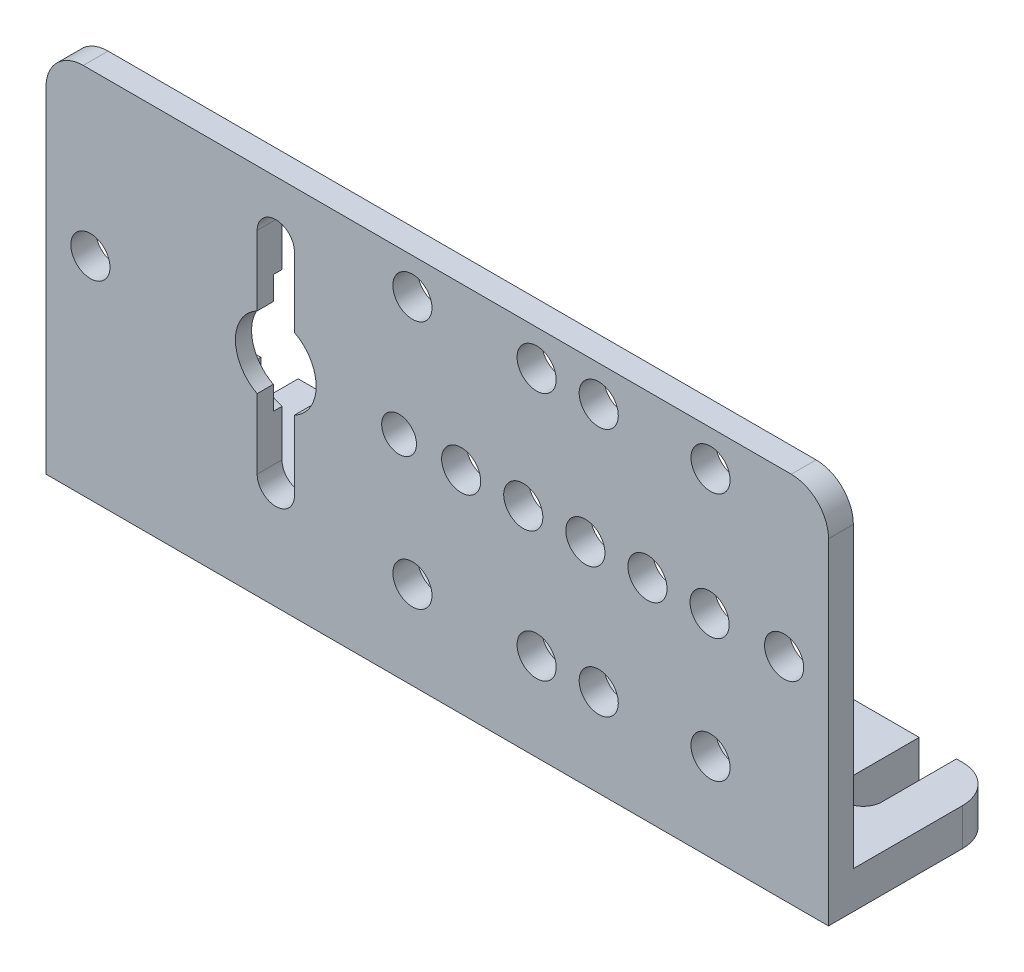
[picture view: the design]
ISO-10303-21;
HEADER;
FILE_DESCRIPTION(('STEP AP214'),'2;1');
FILE_NAME('part.step','',(''),(''),'','','');
FILE_SCHEMA(('AUTOMOTIVE_DESIGN { 1 0 10303 214 1 1 1 1 }'));
ENDSEC;
DATA;
#1=APPLICATION_CONTEXT('core data for automotive mechanical design processes');
#2=APPLICATION_PROTOCOL_DEFINITION('international standard','automotive_design',2000,#1);
#3=PRODUCT_CONTEXT('',#1,'mechanical');
#4=PRODUCT('Part','Part','',(#3));
#5=PRODUCT_RELATED_PRODUCT_CATEGORY('part','',(#4));
#6=PRODUCT_DEFINITION_FORMATION('','',#4);
#7=PRODUCT_DEFINITION_CONTEXT('part definition',#1,'design');
#8=PRODUCT_DEFINITION('design','',#6,#7);
#9=PRODUCT_DEFINITION_SHAPE('','',#8);
#10=(LENGTH_UNIT() NAMED_UNIT(*) SI_UNIT(.MILLI.,.METRE.));
#11=(NAMED_UNIT(*) PLANE_ANGLE_UNIT() SI_UNIT($,.RADIAN.));
#12=(NAMED_UNIT(*) SI_UNIT($,.STERADIAN.) SOLID_ANGLE_UNIT());
#13=UNCERTAINTY_MEASURE_WITH_UNIT(LENGTH_MEASURE(1.E-05),#10,'distance_accuracy_value','');
#14=(GEOMETRIC_REPRESENTATION_CONTEXT(3) GLOBAL_UNCERTAINTY_ASSIGNED_CONTEXT((#13)) GLOBAL_UNIT_ASSIGNED_CONTEXT((#10,
#11,#12)) REPRESENTATION_CONTEXT('',''));
#15=CARTESIAN_POINT('',(0.,0.,0.));
#16=DIRECTION('',(0.,0.,1.));
#17=DIRECTION('',(1.,0.,0.));
#18=AXIS2_PLACEMENT_3D('',#15,#16,#17);
#19=CARTESIAN_POINT('',(3.,3.,-13.8));
#20=DIRECTION('',(0.,0.,1.));
#21=DIRECTION('',(-1.,0.,0.));
#22=AXIS2_PLACEMENT_3D('',#19,#20,#21);
#23=PLANE('',#22);
#24=DIRECTION('',(1.,0.,0.));
#25=VECTOR('',#24,1.);
#26=CARTESIAN_POINT('',(3.,0.,-13.8));
#27=LINE('',#26,#25);
#28=CARTESIAN_POINT('',(6.5,0.,-13.8));
#29=VERTEX_POINT('',#28);
#30=CARTESIAN_POINT('',(56.5,0.,-13.8));
#31=VERTEX_POINT('',#30);
#32=EDGE_CURVE('E392',#29,#31,#27,.T.);
#33=ORIENTED_EDGE('',*,*,#32,.F.);
#34=DIRECTION('',(0.,1.,0.));
#35=VECTOR('',#34,1.);
#36=CARTESIAN_POINT('',(6.5,0.,-13.8));
#37=LINE('',#36,#35);
#38=CARTESIAN_POINT('',(6.5,3.,-13.8));
#39=VERTEX_POINT('',#38);
#40=EDGE_CURVE('E254',#29,#39,#37,.T.);
#41=ORIENTED_EDGE('',*,*,#40,.T.);
#42=DIRECTION('',(1.,0.,0.));
#43=VECTOR('',#42,1.);
#44=CARTESIAN_POINT('',(3.,3.,-13.8));
#45=LINE('',#44,#43);
#46=CARTESIAN_POINT('',(56.5,3.,-13.8));
#47=VERTEX_POINT('',#46);
#48=EDGE_CURVE('E236',#39,#47,#45,.T.);
#49=ORIENTED_EDGE('',*,*,#48,.T.);
#50=DIRECTION('',(0.,1.,0.));
#51=VECTOR('',#50,1.);
#52=CARTESIAN_POINT('',(56.5,0.,-13.8));
#53=LINE('',#52,#51);
#54=EDGE_CURVE('E244',#31,#47,#53,.T.);
#55=ORIENTED_EDGE('',*,*,#54,.F.);
#56=EDGE_LOOP('',(#33,#41,#49,#55));
#57=FACE_BOUND('',#56,.T.);
#58=ADVANCED_FACE('F35',(#57),#23,.F.);
#59=CARTESIAN_POINT('',(3.,0.,-13.8));
#60=VERTEX_POINT('',#59);
#61=CARTESIAN_POINT('',(3.5,0.,-13.8));
#62=VERTEX_POINT('',#61);
#63=EDGE_CURVE('E390',#60,#62,#27,.T.);
#64=ORIENTED_EDGE('',*,*,#63,.F.);
#65=DIRECTION('',(0.,-1.,0.));
#66=VECTOR('',#65,1.);
#67=CARTESIAN_POINT('',(3.,3.,-13.8));
#68=LINE('',#67,#66);
#69=CARTESIAN_POINT('',(3.,3.,-13.8));
#70=VERTEX_POINT('',#69);
#71=EDGE_CURVE('E369',#70,#60,#68,.T.);
#72=ORIENTED_EDGE('',*,*,#71,.F.);
#73=CARTESIAN_POINT('',(3.5,3.,-13.8));
#74=VERTEX_POINT('',#73);
#75=EDGE_CURVE('E255',#70,#74,#45,.T.);
#76=ORIENTED_EDGE('',*,*,#75,.T.);
#77=DIRECTION('',(0.,1.,0.));
#78=VECTOR('',#77,1.);
#79=CARTESIAN_POINT('',(3.5,0.,-13.8));
#80=LINE('',#79,#78);
#81=EDGE_CURVE('E484',#62,#74,#80,.T.);
#82=ORIENTED_EDGE('',*,*,#81,.F.);
#83=EDGE_LOOP('',(#64,#72,#76,#82));
#84=FACE_BOUND('',#83,.T.);
#85=ADVANCED_FACE('F629',(#84),#23,.F.);
#86=CARTESIAN_POINT('',(60.,27.,-2.));
#87=DIRECTION('',(0.,0.,1.));
#88=DIRECTION('',(-1.,0.,0.));
#89=AXIS2_PLACEMENT_3D('',#86,#87,#88);
#90=CYLINDRICAL_SURFACE('',#89,3.);
#91=CARTESIAN_POINT('',(60.,27.,0.));
#92=DIRECTION('',(0.,0.,1.));
#93=DIRECTION('',(1.,0.,0.));
#94=AXIS2_PLACEMENT_3D('',#91,#92,#93);
#95=CIRCLE('',#94,3.);
#96=CARTESIAN_POINT('',(63.,27.,0.));
#97=VERTEX_POINT('',#96);
#98=CARTESIAN_POINT('',(60.,30.,0.));
#99=VERTEX_POINT('',#98);
#100=EDGE_CURVE('E339',#97,#99,#95,.T.);
#101=ORIENTED_EDGE('',*,*,#100,.F.);
#102=DIRECTION('',(0.,0.,1.));
#103=VECTOR('',#102,1.);
#104=CARTESIAN_POINT('',(63.,27.,-2.));
#105=LINE('',#104,#103);
#106=CARTESIAN_POINT('',(63.,27.,-2.));
#107=VERTEX_POINT('',#106);
#108=EDGE_CURVE('E312',#107,#97,#105,.T.);
#109=ORIENTED_EDGE('',*,*,#108,.F.);
#110=CARTESIAN_POINT('',(60.,27.,-2.));
#111=DIRECTION('',(0.,0.,1.));
#112=DIRECTION('',(1.,0.,0.));
#113=AXIS2_PLACEMENT_3D('',#110,#111,#112);
#114=CIRCLE('',#113,3.);
#115=CARTESIAN_POINT('',(60.,30.,-2.));
#116=VERTEX_POINT('',#115);
#117=EDGE_CURVE('E346',#107,#116,#114,.T.);
#118=ORIENTED_EDGE('',*,*,#117,.T.);
#119=DIRECTION('',(0.,0.,1.));
#120=VECTOR('',#119,1.);
#121=CARTESIAN_POINT('',(60.,30.,-2.));
#122=LINE('',#121,#120);
#123=EDGE_CURVE('E288',#116,#99,#122,.T.);
#124=ORIENTED_EDGE('',*,*,#123,.T.);
#125=EDGE_LOOP('',(#101,#109,#118,#124));
#126=FACE_BOUND('',#125,.T.);
#127=ADVANCED_FACE('F37',(#126),#90,.T.);
#128=CARTESIAN_POINT('',(3.,30.,-2.));
#129=DIRECTION('',(0.,-1.,0.));
#130=DIRECTION('',(1.,0.,0.));
#131=AXIS2_PLACEMENT_3D('',#128,#129,#130);
#132=PLANE('',#131);
#133=DIRECTION('',(-1.,0.,0.));
#134=VECTOR('',#133,1.);
#135=CARTESIAN_POINT('',(3.,30.,0.));
#136=LINE('',#135,#134);
#137=CARTESIAN_POINT('',(3.,30.,0.));
#138=VERTEX_POINT('',#137);
#139=EDGE_CURVE('E335',#99,#138,#136,.T.);
#140=ORIENTED_EDGE('',*,*,#139,.F.);
#141=ORIENTED_EDGE('',*,*,#123,.F.);
#142=DIRECTION('',(-1.,0.,0.));
#143=VECTOR('',#142,1.);
#144=CARTESIAN_POINT('',(3.,30.,-2.));
#145=LINE('',#144,#143);
#146=CARTESIAN_POINT('',(3.,30.,-2.));
#147=VERTEX_POINT('',#146);
#148=EDGE_CURVE('E347',#116,#147,#145,.T.);
#149=ORIENTED_EDGE('',*,*,#148,.T.);
#150=DIRECTION('',(0.,0.,1.));
#151=VECTOR('',#150,1.);
#152=CARTESIAN_POINT('',(3.,30.,-2.));
#153=LINE('',#152,#151);
#154=EDGE_CURVE('E292',#147,#138,#153,.T.);
#155=ORIENTED_EDGE('',*,*,#154,.T.);
#156=EDGE_LOOP('',(#140,#141,#149,#155));
#157=FACE_BOUND('',#156,.T.);
#158=ADVANCED_FACE('F350',(#157),#132,.F.);
#159=CARTESIAN_POINT('',(3.,27.,-2.));
#160=DIRECTION('',(0.,0.,1.));
#161=DIRECTION('',(-1.,0.,0.));
#162=AXIS2_PLACEMENT_3D('',#159,#160,#161);
#163=CYLINDRICAL_SURFACE('',#162,3.);
#164=CARTESIAN_POINT('',(3.,27.,0.));
#165=DIRECTION('',(0.,0.,1.));
#166=DIRECTION('',(-1.,0.,0.));
#167=AXIS2_PLACEMENT_3D('',#164,#165,#166);
#168=CIRCLE('',#167,3.);
#169=CARTESIAN_POINT('',(0.,27.,0.));
#170=VERTEX_POINT('',#169);
#171=EDGE_CURVE('E327',#138,#170,#168,.T.);
#172=ORIENTED_EDGE('',*,*,#171,.F.);
#173=ORIENTED_EDGE('',*,*,#154,.F.);
#174=CARTESIAN_POINT('',(3.,27.,-2.));
#175=DIRECTION('',(0.,0.,1.));
#176=DIRECTION('',(-1.,0.,0.));
#177=AXIS2_PLACEMENT_3D('',#174,#175,#176);
#178=CIRCLE('',#177,3.);
#179=CARTESIAN_POINT('',(0.,27.,-2.));
#180=VERTEX_POINT('',#179);
#181=EDGE_CURVE('E306',#147,#180,#178,.T.);
#182=ORIENTED_EDGE('',*,*,#181,.T.);
#183=DIRECTION('',(0.,0.,1.));
#184=VECTOR('',#183,1.);
#185=CARTESIAN_POINT('',(0.,27.,-2.));
#186=LINE('',#185,#184);
#187=EDGE_CURVE('E300',#180,#170,#186,.T.);
#188=ORIENTED_EDGE('',*,*,#187,.T.);
#189=EDGE_LOOP('',(#172,#173,#182,#188));
#190=FACE_BOUND('',#189,.T.);
#191=ADVANCED_FACE('F325',(#190),#163,.T.);
#192=CARTESIAN_POINT('',(0.,0.,-2.));
#193=DIRECTION('',(1.,0.,0.));
#194=DIRECTION('',(0.,0.,1.));
#195=AXIS2_PLACEMENT_3D('',#192,#193,#194);
#196=PLANE('',#195);
#197=DIRECTION('',(0.,-1.,0.));
#198=VECTOR('',#197,1.);
#199=CARTESIAN_POINT('',(0.,0.,0.));
#200=LINE('',#199,#198);
#201=CARTESIAN_POINT('',(0.,0.,0.));
#202=VERTEX_POINT('',#201);
#203=EDGE_CURVE('E334',#170,#202,#200,.T.);
#204=ORIENTED_EDGE('',*,*,#203,.F.);
#205=ORIENTED_EDGE('',*,*,#187,.F.);
#206=DIRECTION('',(0.,-1.,0.));
#207=VECTOR('',#206,1.);
#208=CARTESIAN_POINT('',(0.,0.,-2.));
#209=LINE('',#208,#207);
#210=CARTESIAN_POINT('',(0.,3.,-2.));
#211=VERTEX_POINT('',#210);
#212=EDGE_CURVE('E303',#180,#211,#209,.T.);
#213=ORIENTED_EDGE('',*,*,#212,.T.);
#214=DIRECTION('',(0.,0.,-1.));
#215=VECTOR('',#214,1.);
#216=CARTESIAN_POINT('',(0.,3.,-2.));
#217=LINE('',#216,#215);
#218=CARTESIAN_POINT('',(0.,3.,-10.8));
#219=VERTEX_POINT('',#218);
#220=EDGE_CURVE('E278',#211,#219,#217,.T.);
#221=ORIENTED_EDGE('',*,*,#220,.T.);
#222=DIRECTION('',(0.,-1.,0.));
#223=VECTOR('',#222,1.);
#224=CARTESIAN_POINT('',(0.,3.,-10.8));
#225=LINE('',#224,#223);
#226=CARTESIAN_POINT('',(0.,0.,-10.8));
#227=VERTEX_POINT('',#226);
#228=EDGE_CURVE('E360',#219,#227,#225,.T.);
#229=ORIENTED_EDGE('',*,*,#228,.T.);
#230=DIRECTION('',(0.,0.,1.));
#231=VECTOR('',#230,1.);
#232=CARTESIAN_POINT('',(0.,0.,-2.));
#233=LINE('',#232,#231);
#234=EDGE_CURVE('E318',#227,#202,#233,.T.);
#235=ORIENTED_EDGE('',*,*,#234,.T.);
#236=EDGE_LOOP('',(#204,#205,#213,#221,#229,#235));
#237=FACE_BOUND('',#236,.T.);
#238=ADVANCED_FACE('F357',(#237),#196,.F.);
#239=CARTESIAN_POINT('',(63.,0.,-2.));
#240=DIRECTION('',(0.,1.,0.));
#241=DIRECTION('',(-1.,0.,0.));
#242=AXIS2_PLACEMENT_3D('',#239,#240,#241);
#243=PLANE('',#242);
#244=CARTESIAN_POINT('',(58.,0.,-7.8));
#245=DIRECTION('',(0.,-1.,0.));
#246=DIRECTION('',(0.,0.,-1.));
#247=AXIS2_PLACEMENT_3D('',#244,#245,#246);
#248=CIRCLE('',#247,1.5);
#249=CARTESIAN_POINT('',(59.5,0.,-7.8));
#250=VERTEX_POINT('',#249);
#251=CARTESIAN_POINT('',(56.5,0.,-7.8));
#252=VERTEX_POINT('',#251);
#253=EDGE_CURVE('E252',#250,#252,#248,.T.);
#254=ORIENTED_EDGE('',*,*,#253,.F.);
#255=DIRECTION('',(0.,0.,1.));
#256=VECTOR('',#255,1.);
#257=CARTESIAN_POINT('',(59.5,0.,-7.8));
#258=LINE('',#257,#256);
#259=CARTESIAN_POINT('',(59.5,0.,-13.8));
#260=VERTEX_POINT('',#259);
#261=EDGE_CURVE('E513',#260,#250,#258,.T.);
#262=ORIENTED_EDGE('',*,*,#261,.F.);
#263=CARTESIAN_POINT('',(60.,0.,-13.8));
#264=VERTEX_POINT('',#263);
#265=EDGE_CURVE('E389',#260,#264,#27,.T.);
#266=ORIENTED_EDGE('',*,*,#265,.T.);
#267=CARTESIAN_POINT('',(60.,0.,-10.8));
#268=DIRECTION('',(0.,-1.,0.));
#269=DIRECTION('',(0.,0.,1.));
#270=AXIS2_PLACEMENT_3D('',#267,#268,#269);
#271=CIRCLE('',#270,3.);
#272=CARTESIAN_POINT('',(63.,0.,-10.8));
#273=VERTEX_POINT('',#272);
#274=EDGE_CURVE('E281',#264,#273,#271,.T.);
#275=ORIENTED_EDGE('',*,*,#274,.T.);
#276=DIRECTION('',(0.,0.,1.));
#277=VECTOR('',#276,1.);
#278=CARTESIAN_POINT('',(63.,0.,-2.));
#279=LINE('',#278,#277);
#280=CARTESIAN_POINT('',(63.,0.,0.));
#281=VERTEX_POINT('',#280);
#282=EDGE_CURVE('E315',#273,#281,#279,.T.);
#283=ORIENTED_EDGE('',*,*,#282,.T.);
#284=DIRECTION('',(1.,0.,0.));
#285=VECTOR('',#284,1.);
#286=CARTESIAN_POINT('',(63.,0.,0.));
#287=LINE('',#286,#285);
#288=EDGE_CURVE('E337',#202,#281,#287,.T.);
#289=ORIENTED_EDGE('',*,*,#288,.F.);
#290=ORIENTED_EDGE('',*,*,#234,.F.);
#291=CARTESIAN_POINT('',(3.,0.,-10.8));
#292=DIRECTION('',(0.,-1.,0.));
#293=DIRECTION('',(0.,0.,1.));
#294=AXIS2_PLACEMENT_3D('',#291,#292,#293);
#295=CIRCLE('',#294,3.);
#296=EDGE_CURVE('E367',#227,#60,#295,.T.);
#297=ORIENTED_EDGE('',*,*,#296,.T.);
#298=ORIENTED_EDGE('',*,*,#63,.T.);
#299=DIRECTION('',(0.,0.,-1.));
#300=VECTOR('',#299,1.);
#301=CARTESIAN_POINT('',(3.5,0.,-13.8));
#302=LINE('',#301,#300);
#303=CARTESIAN_POINT('',(3.5,0.,-7.8));
#304=VERTEX_POINT('',#303);
#305=EDGE_CURVE('E487',#304,#62,#302,.T.);
#306=ORIENTED_EDGE('',*,*,#305,.F.);
#307=CARTESIAN_POINT('',(5.,0.,-7.8));
#308=DIRECTION('',(0.,-1.,0.));
#309=DIRECTION('',(0.,0.,1.));
#310=AXIS2_PLACEMENT_3D('',#307,#308,#309);
#311=CIRCLE('',#310,1.5);
#312=CARTESIAN_POINT('',(6.5,0.,-7.8));
#313=VERTEX_POINT('',#312);
#314=EDGE_CURVE('E494',#313,#304,#311,.T.);
#315=ORIENTED_EDGE('',*,*,#314,.F.);
#316=DIRECTION('',(0.,0.,1.));
#317=VECTOR('',#316,1.);
#318=CARTESIAN_POINT('',(6.5,0.,-13.8));
#319=LINE('',#318,#317);
#320=EDGE_CURVE('E497',#29,#313,#319,.T.);
#321=ORIENTED_EDGE('',*,*,#320,.F.);
#322=ORIENTED_EDGE('',*,*,#32,.T.);
#323=DIRECTION('',(0.,0.,-1.));
#324=VECTOR('',#323,1.);
#325=CARTESIAN_POINT('',(56.5,0.,-13.8));
#326=LINE('',#325,#324);
#327=EDGE_CURVE('E247',#252,#31,#326,.T.);
#328=ORIENTED_EDGE('',*,*,#327,.F.);
#329=EDGE_LOOP('',(#254,#262,#266,#275,#283,#289,#290,#297,#298,#306,#315,#321,#322,#328));
#330=FACE_BOUND('',#329,.T.);
#331=ADVANCED_FACE('F387',(#330),#243,.F.);
#332=CARTESIAN_POINT('',(63.,27.,-2.));
#333=DIRECTION('',(-1.,0.,0.));
#334=DIRECTION('',(0.,0.,-1.));
#335=AXIS2_PLACEMENT_3D('',#332,#333,#334);
#336=PLANE('',#335);
#337=DIRECTION('',(0.,1.,0.));
#338=VECTOR('',#337,1.);
#339=CARTESIAN_POINT('',(63.,27.,0.));
#340=LINE('',#339,#338);
#341=EDGE_CURVE('E344',#281,#97,#340,.T.);
#342=ORIENTED_EDGE('',*,*,#341,.F.);
#343=ORIENTED_EDGE('',*,*,#282,.F.);
#344=DIRECTION('',(0.,-1.,0.));
#345=VECTOR('',#344,1.);
#346=CARTESIAN_POINT('',(63.,3.,-10.8));
#347=LINE('',#346,#345);
#348=CARTESIAN_POINT('',(63.,3.,-10.8));
#349=VERTEX_POINT('',#348);
#350=EDGE_CURVE('E269',#349,#273,#347,.T.);
#351=ORIENTED_EDGE('',*,*,#350,.F.);
#352=DIRECTION('',(0.,0.,1.));
#353=VECTOR('',#352,1.);
#354=CARTESIAN_POINT('',(63.,3.,-2.));
#355=LINE('',#354,#353);
#356=CARTESIAN_POINT('',(63.,3.,-2.));
#357=VERTEX_POINT('',#356);
#358=EDGE_CURVE('E266',#349,#357,#355,.T.);
#359=ORIENTED_EDGE('',*,*,#358,.T.);
#360=DIRECTION('',(0.,1.,0.));
#361=VECTOR('',#360,1.);
#362=CARTESIAN_POINT('',(63.,27.,-2.));
#363=LINE('',#362,#361);
#364=EDGE_CURVE('E275',#357,#107,#363,.T.);
#365=ORIENTED_EDGE('',*,*,#364,.T.);
#366=ORIENTED_EDGE('',*,*,#108,.T.);
#367=EDGE_LOOP('',(#342,#343,#351,#359,#365,#366));
#368=FACE_BOUND('',#367,.T.);
#369=ADVANCED_FACE('F384',(#368),#336,.F.);
#370=CARTESIAN_POINT('',(60.,27.,-2.));
#371=DIRECTION('',(0.,0.,-1.));
#372=DIRECTION('',(1.,0.,0.));
#373=AXIS2_PLACEMENT_3D('',#370,#371,#372);
#374=PLANE('',#373);
#375=CARTESIAN_POINT('',(53.5,7.075,-2.));
#376=DIRECTION('',(0.,0.,1.));
#377=DIRECTION('',(1.,0.,0.));
#378=AXIS2_PLACEMENT_3D('',#375,#376,#377);
#379=CIRCLE('',#378,1.575);
#380=CARTESIAN_POINT('',(55.075,7.075,-2.));
#381=VERTEX_POINT('',#380);
#382=EDGE_CURVE('E611',#381,#381,#379,.T.);
#383=ORIENTED_EDGE('',*,*,#382,.T.);
#384=EDGE_LOOP('',(#383));
#385=FACE_BOUND('',#384,.T.);
#386=CARTESIAN_POINT('',(53.5,27.125,-2.));
#387=DIRECTION('',(0.,0.,1.));
#388=DIRECTION('',(1.,0.,0.));
#389=AXIS2_PLACEMENT_3D('',#386,#387,#388);
#390=CIRCLE('',#389,1.575);
#391=CARTESIAN_POINT('',(55.075,27.125,-2.));
#392=VERTEX_POINT('',#391);
#393=EDGE_CURVE('E605',#392,#392,#390,.T.);
#394=ORIENTED_EDGE('',*,*,#393,.T.);
#395=EDGE_LOOP('',(#394));
#396=FACE_BOUND('',#395,.T.);
#397=CARTESIAN_POINT('',(59.425,17.,-2.));
#398=DIRECTION('',(0.,0.,1.));
#399=DIRECTION('',(1.,0.,0.));
#400=AXIS2_PLACEMENT_3D('',#397,#398,#399);
#401=CIRCLE('',#400,1.575);
#402=CARTESIAN_POINT('',(61.,17.,-2.));
#403=VERTEX_POINT('',#402);
#404=EDGE_CURVE('E599',#403,#403,#401,.T.);
#405=ORIENTED_EDGE('',*,*,#404,.T.);
#406=EDGE_LOOP('',(#405));
#407=FACE_BOUND('',#406,.T.);
#408=CARTESIAN_POINT('',(44.5,27.125,-2.));
#409=DIRECTION('',(0.,0.,1.));
#410=DIRECTION('',(1.,0.,0.));
#411=AXIS2_PLACEMENT_3D('',#408,#409,#410);
#412=CIRCLE('',#411,1.57499999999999);
#413=CARTESIAN_POINT('',(46.075,27.125,-2.));
#414=VERTEX_POINT('',#413);
#415=EDGE_CURVE('E593',#414,#414,#412,.T.);
#416=ORIENTED_EDGE('',*,*,#415,.T.);
#417=EDGE_LOOP('',(#416));
#418=FACE_BOUND('',#417,.T.);
#419=CARTESIAN_POINT('',(39.5,27.125,-2.));
#420=DIRECTION('',(0.,0.,1.));
#421=DIRECTION('',(1.,0.,0.));
#422=AXIS2_PLACEMENT_3D('',#419,#420,#421);
#423=CIRCLE('',#422,1.575);
#424=CARTESIAN_POINT('',(41.075,27.125,-2.));
#425=VERTEX_POINT('',#424);
#426=EDGE_CURVE('E587',#425,#425,#423,.T.);
#427=ORIENTED_EDGE('',*,*,#426,.T.);
#428=EDGE_LOOP('',(#427));
#429=FACE_BOUND('',#428,.T.);
#430=CARTESIAN_POINT('',(29.5,27.125,-2.));
#431=DIRECTION('',(0.,0.,1.));
#432=DIRECTION('',(1.,0.,0.));
#433=AXIS2_PLACEMENT_3D('',#430,#431,#432);
#434=CIRCLE('',#433,1.575);
#435=CARTESIAN_POINT('',(31.075,27.125,-2.));
#436=VERTEX_POINT('',#435);
#437=EDGE_CURVE('E581',#436,#436,#434,.T.);
#438=ORIENTED_EDGE('',*,*,#437,.T.);
#439=EDGE_LOOP('',(#438));
#440=FACE_BOUND('',#439,.T.);
#441=CARTESIAN_POINT('',(29.5,7.075,-2.));
#442=DIRECTION('',(0.,0.,1.));
#443=DIRECTION('',(1.,0.,0.));
#444=AXIS2_PLACEMENT_3D('',#441,#442,#443);
#445=CIRCLE('',#444,1.575);
#446=CARTESIAN_POINT('',(31.075,7.075,-2.));
#447=VERTEX_POINT('',#446);
#448=EDGE_CURVE('E575',#447,#447,#445,.T.);
#449=ORIENTED_EDGE('',*,*,#448,.T.);
#450=EDGE_LOOP('',(#449));
#451=FACE_BOUND('',#450,.T.);
#452=CARTESIAN_POINT('',(39.5,7.075,-2.));
#453=DIRECTION('',(0.,0.,1.));
#454=DIRECTION('',(1.,0.,0.));
#455=AXIS2_PLACEMENT_3D('',#452,#453,#454);
#456=CIRCLE('',#455,1.575);
#457=CARTESIAN_POINT('',(41.075,7.075,-2.));
#458=VERTEX_POINT('',#457);
#459=EDGE_CURVE('E569',#458,#458,#456,.T.);
#460=ORIENTED_EDGE('',*,*,#459,.T.);
#461=EDGE_LOOP('',(#460));
#462=FACE_BOUND('',#461,.T.);
#463=CARTESIAN_POINT('',(44.5,7.075,-2.));
#464=DIRECTION('',(0.,0.,1.));
#465=DIRECTION('',(1.,0.,0.));
#466=AXIS2_PLACEMENT_3D('',#463,#464,#465);
#467=CIRCLE('',#466,1.57499999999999);
#468=CARTESIAN_POINT('',(46.075,7.075,-2.));
#469=VERTEX_POINT('',#468);
#470=EDGE_CURVE('E563',#469,#469,#467,.T.);
#471=ORIENTED_EDGE('',*,*,#470,.T.);
#472=EDGE_LOOP('',(#471));
#473=FACE_BOUND('',#472,.T.);
#474=CARTESIAN_POINT('',(53.425,17.,-2.));
#475=DIRECTION('',(0.,0.,1.));
#476=DIRECTION('',(1.,0.,0.));
#477=AXIS2_PLACEMENT_3D('',#474,#475,#476);
#478=CIRCLE('',#477,1.575);
#479=CARTESIAN_POINT('',(55.,17.,-2.));
#480=VERTEX_POINT('',#479);
#481=EDGE_CURVE('E557',#480,#480,#478,.T.);
#482=ORIENTED_EDGE('',*,*,#481,.T.);
#483=EDGE_LOOP('',(#482));
#484=FACE_BOUND('',#483,.T.);
#485=CARTESIAN_POINT('',(48.425,17.,-2.));
#486=DIRECTION('',(0.,0.,1.));
#487=DIRECTION('',(1.,0.,0.));
#488=AXIS2_PLACEMENT_3D('',#485,#486,#487);
#489=CIRCLE('',#488,1.575);
#490=CARTESIAN_POINT('',(50.,17.,-2.));
#491=VERTEX_POINT('',#490);
#492=EDGE_CURVE('E551',#491,#491,#489,.T.);
#493=ORIENTED_EDGE('',*,*,#492,.T.);
#494=EDGE_LOOP('',(#493));
#495=FACE_BOUND('',#494,.T.);
#496=CARTESIAN_POINT('',(43.425,17.,-2.));
#497=DIRECTION('',(0.,0.,1.));
#498=DIRECTION('',(1.,0.,0.));
#499=AXIS2_PLACEMENT_3D('',#496,#497,#498);
#500=CIRCLE('',#499,1.575);
#501=CARTESIAN_POINT('',(45.,17.,-2.));
#502=VERTEX_POINT('',#501);
#503=EDGE_CURVE('E545',#502,#502,#500,.T.);
#504=ORIENTED_EDGE('',*,*,#503,.T.);
#505=EDGE_LOOP('',(#504));
#506=FACE_BOUND('',#505,.T.);
#507=CARTESIAN_POINT('',(38.425,17.,-2.));
#508=DIRECTION('',(0.,0.,1.));
#509=DIRECTION('',(1.,0.,0.));
#510=AXIS2_PLACEMENT_3D('',#507,#508,#509);
#511=CIRCLE('',#510,1.575);
#512=CARTESIAN_POINT('',(40.,17.,-2.));
#513=VERTEX_POINT('',#512);
#514=EDGE_CURVE('E539',#513,#513,#511,.T.);
#515=ORIENTED_EDGE('',*,*,#514,.T.);
#516=EDGE_LOOP('',(#515));
#517=FACE_BOUND('',#516,.T.);
#518=CARTESIAN_POINT('',(33.425,17.,-2.));
#519=DIRECTION('',(0.,0.,1.));
#520=DIRECTION('',(1.,0.,0.));
#521=AXIS2_PLACEMENT_3D('',#518,#519,#520);
#522=CIRCLE('',#521,1.575);
#523=CARTESIAN_POINT('',(35.,17.,-2.));
#524=VERTEX_POINT('',#523);
#525=EDGE_CURVE('E533',#524,#524,#522,.T.);
#526=ORIENTED_EDGE('',*,*,#525,.T.);
#527=EDGE_LOOP('',(#526));
#528=FACE_BOUND('',#527,.T.);
#529=CARTESIAN_POINT('',(28.425,17.,-2.));
#530=DIRECTION('',(0.,0.,1.));
#531=DIRECTION('',(1.,0.,0.));
#532=AXIS2_PLACEMENT_3D('',#529,#530,#531);
#533=CIRCLE('',#532,1.4);
#534=CARTESIAN_POINT('',(29.825,17.,-2.));
#535=VERTEX_POINT('',#534);
#536=EDGE_CURVE('E527',#535,#535,#533,.T.);
#537=ORIENTED_EDGE('',*,*,#536,.T.);
#538=EDGE_LOOP('',(#537));
#539=FACE_BOUND('',#538,.T.);
#540=CARTESIAN_POINT('',(3.575,17.,-2.));
#541=DIRECTION('',(0.,0.,1.));
#542=DIRECTION('',(1.,0.,0.));
#543=AXIS2_PLACEMENT_3D('',#540,#541,#542);
#544=CIRCLE('',#543,1.575);
#545=CARTESIAN_POINT('',(5.15,17.,-2.));
#546=VERTEX_POINT('',#545);
#547=EDGE_CURVE('E521',#546,#546,#544,.T.);
#548=ORIENTED_EDGE('',*,*,#547,.T.);
#549=EDGE_LOOP('',(#548));
#550=FACE_BOUND('',#549,.T.);
#551=CARTESIAN_POINT('',(18.5,17.,-2.));
#552=DIRECTION('',(0.,0.,1.));
#553=DIRECTION('',(1.,0.,0.));
#554=AXIS2_PLACEMENT_3D('',#551,#552,#553);
#555=CIRCLE('',#554,5.00000000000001);
#556=CARTESIAN_POINT('',(17.,21.7696960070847,-2.));
#557=VERTEX_POINT('',#556);
#558=CARTESIAN_POINT('',(17.,12.2303039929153,-2.));
#559=VERTEX_POINT('',#558);
#560=EDGE_CURVE('E477',#557,#559,#555,.T.);
#561=ORIENTED_EDGE('',*,*,#560,.T.);
#562=DIRECTION('',(0.,-1.,0.));
#563=VECTOR('',#562,1.);
#564=CARTESIAN_POINT('',(17.,14.1168593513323,-2.));
#565=LINE('',#564,#563);
#566=CARTESIAN_POINT('',(17.,8.50000000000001,-2.));
#567=VERTEX_POINT('',#566);
#568=EDGE_CURVE('E455',#559,#567,#565,.T.);
#569=ORIENTED_EDGE('',*,*,#568,.T.);
#570=CARTESIAN_POINT('',(18.5,8.50000000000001,-2.));
#571=DIRECTION('',(0.,0.,1.));
#572=DIRECTION('',(1.,0.,0.));
#573=AXIS2_PLACEMENT_3D('',#570,#571,#572);
#574=CIRCLE('',#573,1.5);
#575=CARTESIAN_POINT('',(20.,8.50000000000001,-2.));
#576=VERTEX_POINT('',#575);
#577=EDGE_CURVE('E452',#567,#576,#574,.T.);
#578=ORIENTED_EDGE('',*,*,#577,.T.);
#579=DIRECTION('',(0.,1.,0.));
#580=VECTOR('',#579,1.);
#581=CARTESIAN_POINT('',(20.,14.1168593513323,-2.));
#582=LINE('',#581,#580);
#583=CARTESIAN_POINT('',(20.,12.2303039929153,-2.));
#584=VERTEX_POINT('',#583);
#585=EDGE_CURVE('E449',#576,#584,#582,.T.);
#586=ORIENTED_EDGE('',*,*,#585,.T.);
#587=CARTESIAN_POINT('',(20.,21.7696960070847,-2.));
#588=VERTEX_POINT('',#587);
#589=EDGE_CURVE('E478',#584,#588,#555,.T.);
#590=ORIENTED_EDGE('',*,*,#589,.T.);
#591=DIRECTION('',(0.,1.,0.));
#592=VECTOR('',#591,1.);
#593=CARTESIAN_POINT('',(20.,25.5,-2.));
#594=LINE('',#593,#592);
#595=CARTESIAN_POINT('',(20.,25.5,-2.));
#596=VERTEX_POINT('',#595);
#597=EDGE_CURVE('E446',#588,#596,#594,.T.);
#598=ORIENTED_EDGE('',*,*,#597,.T.);
#599=CARTESIAN_POINT('',(18.5,25.5,-2.));
#600=DIRECTION('',(0.,0.,1.));
#601=DIRECTION('',(1.,0.,0.));
#602=AXIS2_PLACEMENT_3D('',#599,#600,#601);
#603=CIRCLE('',#602,1.5);
#604=CARTESIAN_POINT('',(17.,25.5,-2.));
#605=VERTEX_POINT('',#604);
#606=EDGE_CURVE('E443',#596,#605,#603,.T.);
#607=ORIENTED_EDGE('',*,*,#606,.T.);
#608=DIRECTION('',(0.,-1.,0.));
#609=VECTOR('',#608,1.);
#610=CARTESIAN_POINT('',(17.,25.5,-2.));
#611=LINE('',#610,#609);
#612=EDGE_CURVE('E440',#605,#557,#611,.T.);
#613=ORIENTED_EDGE('',*,*,#612,.T.);
#614=EDGE_LOOP('',(#561,#569,#578,#586,#590,#598,#607,#613));
#615=FACE_BOUND('',#614,.T.);
#616=DIRECTION('',(-1.,0.,0.));
#617=VECTOR('',#616,1.);
#618=CARTESIAN_POINT('',(0.,3.,-2.));
#619=LINE('',#618,#617);
#620=EDGE_CURVE('E272',#357,#211,#619,.T.);
#621=ORIENTED_EDGE('',*,*,#620,.T.);
#622=ORIENTED_EDGE('',*,*,#212,.F.);
#623=ORIENTED_EDGE('',*,*,#181,.F.);
#624=ORIENTED_EDGE('',*,*,#148,.F.);
#625=ORIENTED_EDGE('',*,*,#117,.F.);
#626=ORIENTED_EDGE('',*,*,#364,.F.);
#627=EDGE_LOOP('',(#621,#622,#623,#624,#625,#626));
#628=FACE_BOUND('',#627,.T.);
#629=ADVANCED_FACE('F353',(#385,#396,#407,#418,#429,#440,#451,#462,#473,#484,#495,#506,#517,
#528,#539,#550,#615,#628),#374,.T.);
#630=CARTESIAN_POINT('',(60.,27.,0.));
#631=DIRECTION('',(0.,0.,-1.));
#632=DIRECTION('',(1.,0.,0.));
#633=AXIS2_PLACEMENT_3D('',#630,#631,#632);
#634=PLANE('',#633);
#635=CARTESIAN_POINT('',(53.5,7.075,0.));
#636=DIRECTION('',(0.,0.,1.));
#637=DIRECTION('',(1.,0.,0.));
#638=AXIS2_PLACEMENT_3D('',#635,#636,#637);
#639=CIRCLE('',#638,1.575);
#640=CARTESIAN_POINT('',(55.075,7.075,0.));
#641=VERTEX_POINT('',#640);
#642=EDGE_CURVE('E608',#641,#641,#639,.T.);
#643=ORIENTED_EDGE('',*,*,#642,.F.);
#644=EDGE_LOOP('',(#643));
#645=FACE_BOUND('',#644,.T.);
#646=CARTESIAN_POINT('',(53.5,27.125,0.));
#647=DIRECTION('',(0.,0.,1.));
#648=DIRECTION('',(1.,0.,0.));
#649=AXIS2_PLACEMENT_3D('',#646,#647,#648);
#650=CIRCLE('',#649,1.575);
#651=CARTESIAN_POINT('',(55.075,27.125,0.));
#652=VERTEX_POINT('',#651);
#653=EDGE_CURVE('E602',#652,#652,#650,.T.);
#654=ORIENTED_EDGE('',*,*,#653,.F.);
#655=EDGE_LOOP('',(#654));
#656=FACE_BOUND('',#655,.T.);
#657=CARTESIAN_POINT('',(59.425,17.,0.));
#658=DIRECTION('',(0.,0.,1.));
#659=DIRECTION('',(1.,0.,0.));
#660=AXIS2_PLACEMENT_3D('',#657,#658,#659);
#661=CIRCLE('',#660,1.575);
#662=CARTESIAN_POINT('',(61.,17.,0.));
#663=VERTEX_POINT('',#662);
#664=EDGE_CURVE('E596',#663,#663,#661,.T.);
#665=ORIENTED_EDGE('',*,*,#664,.F.);
#666=EDGE_LOOP('',(#665));
#667=FACE_BOUND('',#666,.T.);
#668=CARTESIAN_POINT('',(44.5,27.125,0.));
#669=DIRECTION('',(0.,0.,1.));
#670=DIRECTION('',(1.,0.,0.));
#671=AXIS2_PLACEMENT_3D('',#668,#669,#670);
#672=CIRCLE('',#671,1.57499999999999);
#673=CARTESIAN_POINT('',(46.075,27.125,0.));
#674=VERTEX_POINT('',#673);
#675=EDGE_CURVE('E590',#674,#674,#672,.T.);
#676=ORIENTED_EDGE('',*,*,#675,.F.);
#677=EDGE_LOOP('',(#676));
#678=FACE_BOUND('',#677,.T.);
#679=CARTESIAN_POINT('',(39.5,27.125,0.));
#680=DIRECTION('',(0.,0.,1.));
#681=DIRECTION('',(1.,0.,0.));
#682=AXIS2_PLACEMENT_3D('',#679,#680,#681);
#683=CIRCLE('',#682,1.575);
#684=CARTESIAN_POINT('',(41.075,27.125,0.));
#685=VERTEX_POINT('',#684);
#686=EDGE_CURVE('E584',#685,#685,#683,.T.);
#687=ORIENTED_EDGE('',*,*,#686,.F.);
#688=EDGE_LOOP('',(#687));
#689=FACE_BOUND('',#688,.T.);
#690=CARTESIAN_POINT('',(29.5,27.125,0.));
#691=DIRECTION('',(0.,0.,1.));
#692=DIRECTION('',(1.,0.,0.));
#693=AXIS2_PLACEMENT_3D('',#690,#691,#692);
#694=CIRCLE('',#693,1.575);
#695=CARTESIAN_POINT('',(31.075,27.125,0.));
#696=VERTEX_POINT('',#695);
#697=EDGE_CURVE('E578',#696,#696,#694,.T.);
#698=ORIENTED_EDGE('',*,*,#697,.F.);
#699=EDGE_LOOP('',(#698));
#700=FACE_BOUND('',#699,.T.);
#701=CARTESIAN_POINT('',(29.5,7.075,0.));
#702=DIRECTION('',(0.,0.,1.));
#703=DIRECTION('',(1.,0.,0.));
#704=AXIS2_PLACEMENT_3D('',#701,#702,#703);
#705=CIRCLE('',#704,1.575);
#706=CARTESIAN_POINT('',(31.075,7.075,0.));
#707=VERTEX_POINT('',#706);
#708=EDGE_CURVE('E572',#707,#707,#705,.T.);
#709=ORIENTED_EDGE('',*,*,#708,.F.);
#710=EDGE_LOOP('',(#709));
#711=FACE_BOUND('',#710,.T.);
#712=CARTESIAN_POINT('',(39.5,7.075,0.));
#713=DIRECTION('',(0.,0.,1.));
#714=DIRECTION('',(1.,0.,0.));
#715=AXIS2_PLACEMENT_3D('',#712,#713,#714);
#716=CIRCLE('',#715,1.575);
#717=CARTESIAN_POINT('',(41.075,7.075,0.));
#718=VERTEX_POINT('',#717);
#719=EDGE_CURVE('E566',#718,#718,#716,.T.);
#720=ORIENTED_EDGE('',*,*,#719,.F.);
#721=EDGE_LOOP('',(#720));
#722=FACE_BOUND('',#721,.T.);
#723=CARTESIAN_POINT('',(44.5,7.075,0.));
#724=DIRECTION('',(0.,0.,1.));
#725=DIRECTION('',(1.,0.,0.));
#726=AXIS2_PLACEMENT_3D('',#723,#724,#725);
#727=CIRCLE('',#726,1.57499999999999);
#728=CARTESIAN_POINT('',(46.075,7.075,0.));
#729=VERTEX_POINT('',#728);
#730=EDGE_CURVE('E560',#729,#729,#727,.T.);
#731=ORIENTED_EDGE('',*,*,#730,.F.);
#732=EDGE_LOOP('',(#731));
#733=FACE_BOUND('',#732,.T.);
#734=CARTESIAN_POINT('',(53.425,17.,0.));
#735=DIRECTION('',(0.,0.,1.));
#736=DIRECTION('',(1.,0.,0.));
#737=AXIS2_PLACEMENT_3D('',#734,#735,#736);
#738=CIRCLE('',#737,1.575);
#739=CARTESIAN_POINT('',(55.,17.,0.));
#740=VERTEX_POINT('',#739);
#741=EDGE_CURVE('E554',#740,#740,#738,.T.);
#742=ORIENTED_EDGE('',*,*,#741,.F.);
#743=EDGE_LOOP('',(#742));
#744=FACE_BOUND('',#743,.T.);
#745=CARTESIAN_POINT('',(48.425,17.,0.));
#746=DIRECTION('',(0.,0.,1.));
#747=DIRECTION('',(1.,0.,0.));
#748=AXIS2_PLACEMENT_3D('',#745,#746,#747);
#749=CIRCLE('',#748,1.575);
#750=CARTESIAN_POINT('',(50.,17.,0.));
#751=VERTEX_POINT('',#750);
#752=EDGE_CURVE('E548',#751,#751,#749,.T.);
#753=ORIENTED_EDGE('',*,*,#752,.F.);
#754=EDGE_LOOP('',(#753));
#755=FACE_BOUND('',#754,.T.);
#756=CARTESIAN_POINT('',(43.425,17.,0.));
#757=DIRECTION('',(0.,0.,1.));
#758=DIRECTION('',(1.,0.,0.));
#759=AXIS2_PLACEMENT_3D('',#756,#757,#758);
#760=CIRCLE('',#759,1.575);
#761=CARTESIAN_POINT('',(45.,17.,0.));
#762=VERTEX_POINT('',#761);
#763=EDGE_CURVE('E542',#762,#762,#760,.T.);
#764=ORIENTED_EDGE('',*,*,#763,.F.);
#765=EDGE_LOOP('',(#764));
#766=FACE_BOUND('',#765,.T.);
#767=CARTESIAN_POINT('',(38.425,17.,0.));
#768=DIRECTION('',(0.,0.,1.));
#769=DIRECTION('',(1.,0.,0.));
#770=AXIS2_PLACEMENT_3D('',#767,#768,#769);
#771=CIRCLE('',#770,1.575);
#772=CARTESIAN_POINT('',(40.,17.,0.));
#773=VERTEX_POINT('',#772);
#774=EDGE_CURVE('E536',#773,#773,#771,.T.);
#775=ORIENTED_EDGE('',*,*,#774,.F.);
#776=EDGE_LOOP('',(#775));
#777=FACE_BOUND('',#776,.T.);
#778=CARTESIAN_POINT('',(33.425,17.,0.));
#779=DIRECTION('',(0.,0.,1.));
#780=DIRECTION('',(1.,0.,0.));
#781=AXIS2_PLACEMENT_3D('',#778,#779,#780);
#782=CIRCLE('',#781,1.575);
#783=CARTESIAN_POINT('',(35.,17.,0.));
#784=VERTEX_POINT('',#783);
#785=EDGE_CURVE('E530',#784,#784,#782,.T.);
#786=ORIENTED_EDGE('',*,*,#785,.F.);
#787=EDGE_LOOP('',(#786));
#788=FACE_BOUND('',#787,.T.);
#789=CARTESIAN_POINT('',(28.425,17.,0.));
#790=DIRECTION('',(0.,0.,1.));
#791=DIRECTION('',(1.,0.,0.));
#792=AXIS2_PLACEMENT_3D('',#789,#790,#791);
#793=CIRCLE('',#792,1.4);
#794=CARTESIAN_POINT('',(29.825,17.,0.));
#795=VERTEX_POINT('',#794);
#796=EDGE_CURVE('E524',#795,#795,#793,.T.);
#797=ORIENTED_EDGE('',*,*,#796,.F.);
#798=EDGE_LOOP('',(#797));
#799=FACE_BOUND('',#798,.T.);
#800=CARTESIAN_POINT('',(3.575,17.,0.));
#801=DIRECTION('',(0.,0.,1.));
#802=DIRECTION('',(1.,0.,0.));
#803=AXIS2_PLACEMENT_3D('',#800,#801,#802);
#804=CIRCLE('',#803,1.575);
#805=CARTESIAN_POINT('',(5.15,17.,0.));
#806=VERTEX_POINT('',#805);
#807=EDGE_CURVE('E241',#806,#806,#804,.T.);
#808=ORIENTED_EDGE('',*,*,#807,.F.);
#809=EDGE_LOOP('',(#808));
#810=FACE_BOUND('',#809,.T.);
#811=DIRECTION('',(0.,-1.,0.));
#812=VECTOR('',#811,1.);
#813=CARTESIAN_POINT('',(17.,25.5,0.));
#814=LINE('',#813,#812);
#815=CARTESIAN_POINT('',(17.,25.5,0.));
#816=VERTEX_POINT('',#815);
#817=CARTESIAN_POINT('',(17.,19.8831406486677,0.));
#818=VERTEX_POINT('',#817);
#819=EDGE_CURVE('E401',#816,#818,#814,.T.);
#820=ORIENTED_EDGE('',*,*,#819,.F.);
#821=CARTESIAN_POINT('',(18.5,25.5,0.));
#822=DIRECTION('',(0.,0.,1.));
#823=DIRECTION('',(1.,0.,0.));
#824=AXIS2_PLACEMENT_3D('',#821,#822,#823);
#825=CIRCLE('',#824,1.5);
#826=CARTESIAN_POINT('',(20.,25.5,0.));
#827=VERTEX_POINT('',#826);
#828=EDGE_CURVE('E419',#827,#816,#825,.T.);
#829=ORIENTED_EDGE('',*,*,#828,.F.);
#830=DIRECTION('',(0.,1.,0.));
#831=VECTOR('',#830,1.);
#832=CARTESIAN_POINT('',(20.,25.5,0.));
#833=LINE('',#832,#831);
#834=CARTESIAN_POINT('',(20.,19.8831406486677,0.));
#835=VERTEX_POINT('',#834);
#836=EDGE_CURVE('E422',#835,#827,#833,.T.);
#837=ORIENTED_EDGE('',*,*,#836,.F.);
#838=CARTESIAN_POINT('',(18.5,17.,0.));
#839=DIRECTION('',(0.,0.,1.));
#840=DIRECTION('',(1.,0.,0.));
#841=AXIS2_PLACEMENT_3D('',#838,#839,#840);
#842=CIRCLE('',#841,3.25);
#843=CARTESIAN_POINT('',(20.,14.1168593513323,0.));
#844=VERTEX_POINT('',#843);
#845=EDGE_CURVE('E425',#844,#835,#842,.T.);
#846=ORIENTED_EDGE('',*,*,#845,.F.);
#847=DIRECTION('',(0.,1.,0.));
#848=VECTOR('',#847,1.);
#849=CARTESIAN_POINT('',(20.,14.1168593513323,0.));
#850=LINE('',#849,#848);
#851=CARTESIAN_POINT('',(20.,8.50000000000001,0.));
#852=VERTEX_POINT('',#851);
#853=EDGE_CURVE('E428',#852,#844,#850,.T.);
#854=ORIENTED_EDGE('',*,*,#853,.F.);
#855=CARTESIAN_POINT('',(18.5,8.50000000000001,0.));
#856=DIRECTION('',(0.,0.,1.));
#857=DIRECTION('',(1.,0.,0.));
#858=AXIS2_PLACEMENT_3D('',#855,#856,#857);
#859=CIRCLE('',#858,1.5);
#860=CARTESIAN_POINT('',(17.,8.50000000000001,0.));
#861=VERTEX_POINT('',#860);
#862=EDGE_CURVE('E431',#861,#852,#859,.T.);
#863=ORIENTED_EDGE('',*,*,#862,.F.);
#864=DIRECTION('',(0.,-1.,0.));
#865=VECTOR('',#864,1.);
#866=CARTESIAN_POINT('',(17.,14.1168593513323,0.));
#867=LINE('',#866,#865);
#868=CARTESIAN_POINT('',(17.,14.1168593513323,0.));
#869=VERTEX_POINT('',#868);
#870=EDGE_CURVE('E434',#869,#861,#867,.T.);
#871=ORIENTED_EDGE('',*,*,#870,.F.);
#872=CARTESIAN_POINT('',(18.5,17.,0.));
#873=DIRECTION('',(0.,0.,1.));
#874=DIRECTION('',(1.,0.,0.));
#875=AXIS2_PLACEMENT_3D('',#872,#873,#874);
#876=CIRCLE('',#875,3.25);
#877=EDGE_CURVE('E437',#818,#869,#876,.T.);
#878=ORIENTED_EDGE('',*,*,#877,.F.);
#879=EDGE_LOOP('',(#820,#829,#837,#846,#854,#863,#871,#878));
#880=FACE_BOUND('',#879,.T.);
#881=ORIENTED_EDGE('',*,*,#100,.T.);
#882=ORIENTED_EDGE('',*,*,#139,.T.);
#883=ORIENTED_EDGE('',*,*,#171,.T.);
#884=ORIENTED_EDGE('',*,*,#203,.T.);
#885=ORIENTED_EDGE('',*,*,#288,.T.);
#886=ORIENTED_EDGE('',*,*,#341,.T.);
#887=EDGE_LOOP('',(#881,#882,#883,#884,#885,#886));
#888=FACE_BOUND('',#887,.T.);
#889=ADVANCED_FACE('F332',(#645,#656,#667,#678,#689,#700,#711,#722,#733,#744,#755,#766,#777,
#788,#799,#810,#880,#888),#634,.F.);
#890=CARTESIAN_POINT('',(3.,3.,-10.8));
#891=DIRECTION('',(0.,-1.,0.));
#892=DIRECTION('',(0.,0.,1.));
#893=AXIS2_PLACEMENT_3D('',#890,#891,#892);
#894=CYLINDRICAL_SURFACE('',#893,3.);
#895=ORIENTED_EDGE('',*,*,#296,.F.);
#896=ORIENTED_EDGE('',*,*,#228,.F.);
#897=CARTESIAN_POINT('',(3.,3.,-10.8));
#898=DIRECTION('',(0.,-1.,0.));
#899=DIRECTION('',(0.,0.,1.));
#900=AXIS2_PLACEMENT_3D('',#897,#898,#899);
#901=CIRCLE('',#900,3.);
#902=EDGE_CURVE('E261',#219,#70,#901,.T.);
#903=ORIENTED_EDGE('',*,*,#902,.T.);
#904=ORIENTED_EDGE('',*,*,#71,.T.);
#905=EDGE_LOOP('',(#895,#896,#903,#904));
#906=FACE_BOUND('',#905,.T.);
#907=ADVANCED_FACE('F366',(#906),#894,.T.);
#908=CARTESIAN_POINT('',(59.5,3.,-13.8));
#909=VERTEX_POINT('',#908);
#910=CARTESIAN_POINT('',(60.,3.,-13.8));
#911=VERTEX_POINT('',#910);
#912=EDGE_CURVE('E256',#909,#911,#45,.T.);
#913=ORIENTED_EDGE('',*,*,#912,.T.);
#914=DIRECTION('',(0.,-1.,0.));
#915=VECTOR('',#914,1.);
#916=CARTESIAN_POINT('',(60.,3.,-13.8));
#917=LINE('',#916,#915);
#918=EDGE_CURVE('E371',#911,#264,#917,.T.);
#919=ORIENTED_EDGE('',*,*,#918,.T.);
#920=ORIENTED_EDGE('',*,*,#265,.F.);
#921=DIRECTION('',(0.,1.,0.));
#922=VECTOR('',#921,1.);
#923=CARTESIAN_POINT('',(59.5,0.,-13.8));
#924=LINE('',#923,#922);
#925=EDGE_CURVE('E251',#260,#909,#924,.T.);
#926=ORIENTED_EDGE('',*,*,#925,.T.);
#927=EDGE_LOOP('',(#913,#919,#920,#926));
#928=FACE_BOUND('',#927,.T.);
#929=ADVANCED_FACE('F631',(#928),#23,.F.);
#930=CARTESIAN_POINT('',(60.,3.,-10.8));
#931=DIRECTION('',(0.,-1.,0.));
#932=DIRECTION('',(0.,0.,1.));
#933=AXIS2_PLACEMENT_3D('',#930,#931,#932);
#934=CYLINDRICAL_SURFACE('',#933,3.);
#935=ORIENTED_EDGE('',*,*,#274,.F.);
#936=ORIENTED_EDGE('',*,*,#918,.F.);
#937=CARTESIAN_POINT('',(60.,3.,-10.8));
#938=DIRECTION('',(0.,-1.,0.));
#939=DIRECTION('',(0.,0.,1.));
#940=AXIS2_PLACEMENT_3D('',#937,#938,#939);
#941=CIRCLE('',#940,3.);
#942=EDGE_CURVE('E259',#911,#349,#941,.T.);
#943=ORIENTED_EDGE('',*,*,#942,.T.);
#944=ORIENTED_EDGE('',*,*,#350,.T.);
#945=EDGE_LOOP('',(#935,#936,#943,#944));
#946=FACE_BOUND('',#945,.T.);
#947=ADVANCED_FACE('F380',(#946),#934,.T.);
#948=CARTESIAN_POINT('',(3.,3.,-10.8));
#949=DIRECTION('',(0.,-1.,0.));
#950=DIRECTION('',(0.,0.,1.));
#951=AXIS2_PLACEMENT_3D('',#948,#949,#950);
#952=PLANE('',#951);
#953=ORIENTED_EDGE('',*,*,#48,.F.);
#954=DIRECTION('',(0.,0.,1.));
#955=VECTOR('',#954,1.);
#956=CARTESIAN_POINT('',(6.5,3.,-13.8));
#957=LINE('',#956,#955);
#958=CARTESIAN_POINT('',(6.5,3.,-7.8));
#959=VERTEX_POINT('',#958);
#960=EDGE_CURVE('E58',#39,#959,#957,.T.);
#961=ORIENTED_EDGE('',*,*,#960,.T.);
#962=CARTESIAN_POINT('',(5.,3.,-7.8));
#963=DIRECTION('',(0.,-1.,0.));
#964=DIRECTION('',(0.,0.,1.));
#965=AXIS2_PLACEMENT_3D('',#962,#963,#964);
#966=CIRCLE('',#965,1.5);
#967=CARTESIAN_POINT('',(3.5,3.,-7.8));
#968=VERTEX_POINT('',#967);
#969=EDGE_CURVE('E502',#959,#968,#966,.T.);
#970=ORIENTED_EDGE('',*,*,#969,.T.);
#971=DIRECTION('',(0.,0.,-1.));
#972=VECTOR('',#971,1.);
#973=CARTESIAN_POINT('',(3.5,3.,-13.8));
#974=LINE('',#973,#972);
#975=EDGE_CURVE('E500',#968,#74,#974,.T.);
#976=ORIENTED_EDGE('',*,*,#975,.T.);
#977=ORIENTED_EDGE('',*,*,#75,.F.);
#978=ORIENTED_EDGE('',*,*,#902,.F.);
#979=ORIENTED_EDGE('',*,*,#220,.F.);
#980=ORIENTED_EDGE('',*,*,#620,.F.);
#981=ORIENTED_EDGE('',*,*,#358,.F.);
#982=ORIENTED_EDGE('',*,*,#942,.F.);
#983=ORIENTED_EDGE('',*,*,#912,.F.);
#984=DIRECTION('',(0.,0.,1.));
#985=VECTOR('',#984,1.);
#986=CARTESIAN_POINT('',(59.5,3.,-7.8));
#987=LINE('',#986,#985);
#988=CARTESIAN_POINT('',(59.5,3.,-7.8));
#989=VERTEX_POINT('',#988);
#990=EDGE_CURVE('E50',#909,#989,#987,.T.);
#991=ORIENTED_EDGE('',*,*,#990,.T.);
#992=CARTESIAN_POINT('',(58.,3.,-7.8));
#993=DIRECTION('',(0.,-1.,0.));
#994=DIRECTION('',(0.,0.,-1.));
#995=AXIS2_PLACEMENT_3D('',#992,#993,#994);
#996=CIRCLE('',#995,1.5);
#997=CARTESIAN_POINT('',(56.5,3.,-7.8));
#998=VERTEX_POINT('',#997);
#999=EDGE_CURVE('E239',#989,#998,#996,.T.);
#1000=ORIENTED_EDGE('',*,*,#999,.T.);
#1001=DIRECTION('',(0.,0.,-1.));
#1002=VECTOR('',#1001,1.);
#1003=CARTESIAN_POINT('',(56.5,3.,-13.8));
#1004=LINE('',#1003,#1002);
#1005=EDGE_CURVE('E232',#998,#47,#1004,.T.);
#1006=ORIENTED_EDGE('',*,*,#1005,.T.);
#1007=EDGE_LOOP('',(#953,#961,#970,#976,#977,#978,#979,#980,#981,#982,#983,#991,#1000,#1006));
#1008=FACE_BOUND('',#1007,.T.);
#1009=ADVANCED_FACE('F234',(#1008),#952,.F.);
#1010=CARTESIAN_POINT('',(18.5,17.,0.));
#1011=DIRECTION('',(0.,0.,-1.));
#1012=DIRECTION('',(1.,0.,0.));
#1013=AXIS2_PLACEMENT_3D('',#1010,#1011,#1012);
#1014=CYLINDRICAL_SURFACE('',#1013,3.25);
#1015=DIRECTION('',(0.,0.,-1.));
#1016=VECTOR('',#1015,1.);
#1017=CARTESIAN_POINT('',(17.,19.8831406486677,0.));
#1018=LINE('',#1017,#1016);
#1019=CARTESIAN_POINT('',(17.,19.8831406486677,-1.29999999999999));
#1020=VERTEX_POINT('',#1019);
#1021=EDGE_CURVE('E396',#818,#1020,#1018,.T.);
#1022=ORIENTED_EDGE('',*,*,#1021,.F.);
#1023=ORIENTED_EDGE('',*,*,#877,.T.);
#1024=DIRECTION('',(0.,0.,-1.));
#1025=VECTOR('',#1024,1.);
#1026=CARTESIAN_POINT('',(17.,14.1168593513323,0.));
#1027=LINE('',#1026,#1025);
#1028=CARTESIAN_POINT('',(17.,14.1168593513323,-1.29999999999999));
#1029=VERTEX_POINT('',#1028);
#1030=EDGE_CURVE('E397',#869,#1029,#1027,.T.);
#1031=ORIENTED_EDGE('',*,*,#1030,.T.);
#1032=CARTESIAN_POINT('',(18.5,17.,-1.29999999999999));
#1033=DIRECTION('',(0.,0.,-1.));
#1034=DIRECTION('',(-1.,0.,0.));
#1035=AXIS2_PLACEMENT_3D('',#1032,#1033,#1034);
#1036=CIRCLE('',#1035,3.25);
#1037=EDGE_CURVE('E475',#1020,#1029,#1036,.F.);
#1038=ORIENTED_EDGE('',*,*,#1037,.F.);
#1039=EDGE_LOOP('',(#1022,#1023,#1031,#1038));
#1040=FACE_BOUND('',#1039,.T.);
#1041=ADVANCED_FACE('F692',(#1040),#1014,.F.);
#1042=CARTESIAN_POINT('',(17.,25.5,0.));
#1043=DIRECTION('',(-1.,0.,0.));
#1044=DIRECTION('',(0.,-1.,0.));
#1045=AXIS2_PLACEMENT_3D('',#1042,#1043,#1044);
#1046=PLANE('',#1045);
#1047=ORIENTED_EDGE('',*,*,#612,.F.);
#1048=DIRECTION('',(0.,0.,-1.));
#1049=VECTOR('',#1048,1.);
#1050=CARTESIAN_POINT('',(17.,25.5,0.));
#1051=LINE('',#1050,#1049);
#1052=EDGE_CURVE('E413',#816,#605,#1051,.T.);
#1053=ORIENTED_EDGE('',*,*,#1052,.F.);
#1054=ORIENTED_EDGE('',*,*,#819,.T.);
#1055=ORIENTED_EDGE('',*,*,#1021,.T.);
#1056=DIRECTION('',(0.,-1.,0.));
#1057=VECTOR('',#1056,1.);
#1058=CARTESIAN_POINT('',(17.,25.5,-1.29999999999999));
#1059=LINE('',#1058,#1057);
#1060=CARTESIAN_POINT('',(17.,21.7696960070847,-1.29999999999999));
#1061=VERTEX_POINT('',#1060);
#1062=EDGE_CURVE('E473',#1061,#1020,#1059,.T.);
#1063=ORIENTED_EDGE('',*,*,#1062,.F.);
#1064=DIRECTION('',(0.,0.,-1.));
#1065=VECTOR('',#1064,1.);
#1066=CARTESIAN_POINT('',(17.,21.7696960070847,-2.));
#1067=LINE('',#1066,#1065);
#1068=EDGE_CURVE('E458',#557,#1061,#1067,.F.);
#1069=ORIENTED_EDGE('',*,*,#1068,.F.);
#1070=EDGE_LOOP('',(#1047,#1053,#1054,#1055,#1063,#1069));
#1071=FACE_BOUND('',#1070,.T.);
#1072=ADVANCED_FACE('F688',(#1071),#1046,.F.);
#1073=CARTESIAN_POINT('',(18.5,25.5,0.));
#1074=DIRECTION('',(0.,0.,-1.));
#1075=DIRECTION('',(1.,0.,0.));
#1076=AXIS2_PLACEMENT_3D('',#1073,#1074,#1075);
#1077=CYLINDRICAL_SURFACE('',#1076,1.5);
#1078=ORIENTED_EDGE('',*,*,#606,.F.);
#1079=DIRECTION('',(0.,0.,-1.));
#1080=VECTOR('',#1079,1.);
#1081=CARTESIAN_POINT('',(20.,25.5,0.));
#1082=LINE('',#1081,#1080);
#1083=EDGE_CURVE('E411',#827,#596,#1082,.T.);
#1084=ORIENTED_EDGE('',*,*,#1083,.F.);
#1085=ORIENTED_EDGE('',*,*,#828,.T.);
#1086=ORIENTED_EDGE('',*,*,#1052,.T.);
#1087=EDGE_LOOP('',(#1078,#1084,#1085,#1086));
#1088=FACE_BOUND('',#1087,.T.);
#1089=ADVANCED_FACE('F691',(#1088),#1077,.F.);
#1090=CARTESIAN_POINT('',(20.,25.5,0.));
#1091=DIRECTION('',(1.,0.,0.));
#1092=DIRECTION('',(0.,0.,1.));
#1093=AXIS2_PLACEMENT_3D('',#1090,#1091,#1092);
#1094=PLANE('',#1093);
#1095=DIRECTION('',(0.,1.,0.));
#1096=VECTOR('',#1095,1.);
#1097=CARTESIAN_POINT('',(20.,25.5,-1.29999999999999));
#1098=LINE('',#1097,#1096);
#1099=CARTESIAN_POINT('',(20.,19.8831406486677,-1.29999999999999));
#1100=VERTEX_POINT('',#1099);
#1101=CARTESIAN_POINT('',(20.,21.7696960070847,-1.29999999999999));
#1102=VERTEX_POINT('',#1101);
#1103=EDGE_CURVE('E466',#1100,#1102,#1098,.T.);
#1104=ORIENTED_EDGE('',*,*,#1103,.F.);
#1105=DIRECTION('',(0.,0.,-1.));
#1106=VECTOR('',#1105,1.);
#1107=CARTESIAN_POINT('',(20.,19.8831406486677,0.));
#1108=LINE('',#1107,#1106);
#1109=EDGE_CURVE('E408',#835,#1100,#1108,.T.);
#1110=ORIENTED_EDGE('',*,*,#1109,.F.);
#1111=ORIENTED_EDGE('',*,*,#836,.T.);
#1112=ORIENTED_EDGE('',*,*,#1083,.T.);
#1113=ORIENTED_EDGE('',*,*,#597,.F.);
#1114=DIRECTION('',(0.,0.,-1.));
#1115=VECTOR('',#1114,1.);
#1116=CARTESIAN_POINT('',(20.,21.7696960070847,-2.));
#1117=LINE('',#1116,#1115);
#1118=EDGE_CURVE('E461',#1102,#588,#1117,.T.);
#1119=ORIENTED_EDGE('',*,*,#1118,.F.);
#1120=EDGE_LOOP('',(#1104,#1110,#1111,#1112,#1113,#1119));
#1121=FACE_BOUND('',#1120,.T.);
#1122=ADVANCED_FACE('F696',(#1121),#1094,.F.);
#1123=CARTESIAN_POINT('',(18.5,17.,0.));
#1124=DIRECTION('',(0.,0.,-1.));
#1125=DIRECTION('',(1.,0.,0.));
#1126=AXIS2_PLACEMENT_3D('',#1123,#1124,#1125);
#1127=CYLINDRICAL_SURFACE('',#1126,3.25);
#1128=DIRECTION('',(0.,0.,-1.));
#1129=VECTOR('',#1128,1.);
#1130=CARTESIAN_POINT('',(20.,14.1168593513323,0.));
#1131=LINE('',#1130,#1129);
#1132=CARTESIAN_POINT('',(20.,14.1168593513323,-1.29999999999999));
#1133=VERTEX_POINT('',#1132);
#1134=EDGE_CURVE('E405',#844,#1133,#1131,.T.);
#1135=ORIENTED_EDGE('',*,*,#1134,.F.);
#1136=ORIENTED_EDGE('',*,*,#845,.T.);
#1137=ORIENTED_EDGE('',*,*,#1109,.T.);
#1138=CARTESIAN_POINT('',(18.5,17.,-1.29999999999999));
#1139=DIRECTION('',(0.,0.,-1.));
#1140=DIRECTION('',(-1.,0.,0.));
#1141=AXIS2_PLACEMENT_3D('',#1138,#1139,#1140);
#1142=CIRCLE('',#1141,3.25);
#1143=EDGE_CURVE('E469',#1133,#1100,#1142,.F.);
#1144=ORIENTED_EDGE('',*,*,#1143,.F.);
#1145=EDGE_LOOP('',(#1135,#1136,#1137,#1144));
#1146=FACE_BOUND('',#1145,.T.);
#1147=ADVANCED_FACE('F700',(#1146),#1127,.F.);
#1148=CARTESIAN_POINT('',(20.,14.1168593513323,0.));
#1149=DIRECTION('',(1.,0.,0.));
#1150=DIRECTION('',(0.,0.,1.));
#1151=AXIS2_PLACEMENT_3D('',#1148,#1149,#1150);
#1152=PLANE('',#1151);
#1153=ORIENTED_EDGE('',*,*,#585,.F.);
#1154=DIRECTION('',(0.,0.,-1.));
#1155=VECTOR('',#1154,1.);
#1156=CARTESIAN_POINT('',(20.,8.50000000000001,0.));
#1157=LINE('',#1156,#1155);
#1158=EDGE_CURVE('E403',#852,#576,#1157,.T.);
#1159=ORIENTED_EDGE('',*,*,#1158,.F.);
#1160=ORIENTED_EDGE('',*,*,#853,.T.);
#1161=ORIENTED_EDGE('',*,*,#1134,.T.);
#1162=DIRECTION('',(0.,1.,0.));
#1163=VECTOR('',#1162,1.);
#1164=CARTESIAN_POINT('',(20.,14.1168593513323,-1.29999999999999));
#1165=LINE('',#1164,#1163);
#1166=CARTESIAN_POINT('',(20.,12.2303039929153,-1.29999999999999));
#1167=VERTEX_POINT('',#1166);
#1168=EDGE_CURVE('E471',#1167,#1133,#1165,.T.);
#1169=ORIENTED_EDGE('',*,*,#1168,.F.);
#1170=DIRECTION('',(0.,0.,-1.));
#1171=VECTOR('',#1170,1.);
#1172=CARTESIAN_POINT('',(20.,12.2303039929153,-2.));
#1173=LINE('',#1172,#1171);
#1174=EDGE_CURVE('E463',#584,#1167,#1173,.F.);
#1175=ORIENTED_EDGE('',*,*,#1174,.F.);
#1176=EDGE_LOOP('',(#1153,#1159,#1160,#1161,#1169,#1175));
#1177=FACE_BOUND('',#1176,.T.);
#1178=ADVANCED_FACE('F704',(#1177),#1152,.F.);
#1179=CARTESIAN_POINT('',(18.5,8.50000000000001,0.));
#1180=DIRECTION('',(0.,0.,-1.));
#1181=DIRECTION('',(1.,0.,0.));
#1182=AXIS2_PLACEMENT_3D('',#1179,#1180,#1181);
#1183=CYLINDRICAL_SURFACE('',#1182,1.5);
#1184=ORIENTED_EDGE('',*,*,#577,.F.);
#1185=DIRECTION('',(0.,0.,-1.));
#1186=VECTOR('',#1185,1.);
#1187=CARTESIAN_POINT('',(17.,8.50000000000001,0.));
#1188=LINE('',#1187,#1186);
#1189=EDGE_CURVE('E400',#861,#567,#1188,.T.);
#1190=ORIENTED_EDGE('',*,*,#1189,.F.);
#1191=ORIENTED_EDGE('',*,*,#862,.T.);
#1192=ORIENTED_EDGE('',*,*,#1158,.T.);
#1193=EDGE_LOOP('',(#1184,#1190,#1191,#1192));
#1194=FACE_BOUND('',#1193,.T.);
#1195=ADVANCED_FACE('F708',(#1194),#1183,.F.);
#1196=CARTESIAN_POINT('',(17.,14.1168593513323,0.));
#1197=DIRECTION('',(-1.,0.,0.));
#1198=DIRECTION('',(0.,0.,-1.));
#1199=AXIS2_PLACEMENT_3D('',#1196,#1197,#1198);
#1200=PLANE('',#1199);
#1201=DIRECTION('',(0.,-1.,0.));
#1202=VECTOR('',#1201,1.);
#1203=CARTESIAN_POINT('',(17.,14.1168593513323,-1.29999999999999));
#1204=LINE('',#1203,#1202);
#1205=CARTESIAN_POINT('',(17.,12.2303039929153,-1.29999999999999));
#1206=VERTEX_POINT('',#1205);
#1207=EDGE_CURVE('E43',#1029,#1206,#1204,.T.);
#1208=ORIENTED_EDGE('',*,*,#1207,.F.);
#1209=ORIENTED_EDGE('',*,*,#1030,.F.);
#1210=ORIENTED_EDGE('',*,*,#870,.T.);
#1211=ORIENTED_EDGE('',*,*,#1189,.T.);
#1212=ORIENTED_EDGE('',*,*,#568,.F.);
#1213=DIRECTION('',(0.,0.,-1.));
#1214=VECTOR('',#1213,1.);
#1215=CARTESIAN_POINT('',(17.,12.2303039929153,-2.));
#1216=LINE('',#1215,#1214);
#1217=EDGE_CURVE('E11',#1206,#559,#1216,.T.);
#1218=ORIENTED_EDGE('',*,*,#1217,.F.);
#1219=EDGE_LOOP('',(#1208,#1209,#1210,#1211,#1212,#1218));
#1220=FACE_BOUND('',#1219,.T.);
#1221=ADVANCED_FACE('F712',(#1220),#1200,.F.);
#1222=CARTESIAN_POINT('',(18.5,17.,-1.29999999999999));
#1223=DIRECTION('',(0.,0.,1.));
#1224=DIRECTION('',(-1.,0.,0.));
#1225=AXIS2_PLACEMENT_3D('',#1222,#1223,#1224);
#1226=PLANE('',#1225);
#1227=CARTESIAN_POINT('',(18.5,17.,-1.29999999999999));
#1228=DIRECTION('',(0.,0.,1.));
#1229=DIRECTION('',(1.,0.,0.));
#1230=AXIS2_PLACEMENT_3D('',#1227,#1228,#1229);
#1231=CIRCLE('',#1230,5.00000000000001);
#1232=EDGE_CURVE('E481',#1061,#1206,#1231,.T.);
#1233=ORIENTED_EDGE('',*,*,#1232,.F.);
#1234=ORIENTED_EDGE('',*,*,#1062,.T.);
#1235=ORIENTED_EDGE('',*,*,#1037,.T.);
#1236=ORIENTED_EDGE('',*,*,#1207,.T.);
#1237=EDGE_LOOP('',(#1233,#1234,#1235,#1236));
#1238=FACE_BOUND('',#1237,.T.);
#1239=ADVANCED_FACE('F683',(#1238),#1226,.F.);
#1240=CARTESIAN_POINT('',(18.5,17.,-2.));
#1241=DIRECTION('',(0.,0.,-1.));
#1242=DIRECTION('',(1.,0.,0.));
#1243=AXIS2_PLACEMENT_3D('',#1240,#1241,#1242);
#1244=CYLINDRICAL_SURFACE('',#1243,5.00000000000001);
#1245=ORIENTED_EDGE('',*,*,#560,.F.);
#1246=ORIENTED_EDGE('',*,*,#1068,.T.);
#1247=ORIENTED_EDGE('',*,*,#1232,.T.);
#1248=ORIENTED_EDGE('',*,*,#1217,.T.);
#1249=EDGE_LOOP('',(#1245,#1246,#1247,#1248));
#1250=FACE_BOUND('',#1249,.T.);
#1251=ADVANCED_FACE('F684',(#1250),#1244,.F.);
#1252=EDGE_CURVE('E482',#1167,#1102,#1231,.T.);
#1253=ORIENTED_EDGE('',*,*,#1252,.T.);
#1254=ORIENTED_EDGE('',*,*,#1118,.T.);
#1255=ORIENTED_EDGE('',*,*,#589,.F.);
#1256=ORIENTED_EDGE('',*,*,#1174,.T.);
#1257=EDGE_LOOP('',(#1253,#1254,#1255,#1256));
#1258=FACE_BOUND('',#1257,.T.);
#1259=ADVANCED_FACE('F681',(#1258),#1244,.F.);
#1260=ORIENTED_EDGE('',*,*,#1143,.T.);
#1261=ORIENTED_EDGE('',*,*,#1103,.T.);
#1262=ORIENTED_EDGE('',*,*,#1252,.F.);
#1263=ORIENTED_EDGE('',*,*,#1168,.T.);
#1264=EDGE_LOOP('',(#1260,#1261,#1262,#1263));
#1265=FACE_BOUND('',#1264,.T.);
#1266=ADVANCED_FACE('F674',(#1265),#1226,.F.);
#1267=CARTESIAN_POINT('',(3.5,0.,-13.8));
#1268=DIRECTION('',(-1.,0.,0.));
#1269=DIRECTION('',(0.,0.,-1.));
#1270=AXIS2_PLACEMENT_3D('',#1267,#1268,#1269);
#1271=PLANE('',#1270);
#1272=ORIENTED_EDGE('',*,*,#975,.F.);
#1273=DIRECTION('',(0.,1.,0.));
#1274=VECTOR('',#1273,1.);
#1275=CARTESIAN_POINT('',(3.5,0.,-7.8));
#1276=LINE('',#1275,#1274);
#1277=EDGE_CURVE('E489',#304,#968,#1276,.T.);
#1278=ORIENTED_EDGE('',*,*,#1277,.F.);
#1279=ORIENTED_EDGE('',*,*,#305,.T.);
#1280=ORIENTED_EDGE('',*,*,#81,.T.);
#1281=EDGE_LOOP('',(#1272,#1278,#1279,#1280));
#1282=FACE_BOUND('',#1281,.T.);
#1283=ADVANCED_FACE('F649',(#1282),#1271,.F.);
#1284=CARTESIAN_POINT('',(5.,0.,-7.8));
#1285=DIRECTION('',(0.,1.,0.));
#1286=DIRECTION('',(0.,0.,-1.));
#1287=AXIS2_PLACEMENT_3D('',#1284,#1285,#1286);
#1288=CYLINDRICAL_SURFACE('',#1287,1.5);
#1289=ORIENTED_EDGE('',*,*,#969,.F.);
#1290=DIRECTION('',(0.,1.,0.));
#1291=VECTOR('',#1290,1.);
#1292=CARTESIAN_POINT('',(6.5,0.,-7.8));
#1293=LINE('',#1292,#1291);
#1294=EDGE_CURVE('E486',#313,#959,#1293,.T.);
#1295=ORIENTED_EDGE('',*,*,#1294,.F.);
#1296=ORIENTED_EDGE('',*,*,#314,.T.);
#1297=ORIENTED_EDGE('',*,*,#1277,.T.);
#1298=EDGE_LOOP('',(#1289,#1295,#1296,#1297));
#1299=FACE_BOUND('',#1298,.T.);
#1300=ADVANCED_FACE('F653',(#1299),#1288,.F.);
#1301=CARTESIAN_POINT('',(6.5,0.,-13.8));
#1302=DIRECTION('',(1.,0.,0.));
#1303=DIRECTION('',(0.,0.,1.));
#1304=AXIS2_PLACEMENT_3D('',#1301,#1302,#1303);
#1305=PLANE('',#1304);
#1306=ORIENTED_EDGE('',*,*,#960,.F.);
#1307=ORIENTED_EDGE('',*,*,#40,.F.);
#1308=ORIENTED_EDGE('',*,*,#320,.T.);
#1309=ORIENTED_EDGE('',*,*,#1294,.T.);
#1310=EDGE_LOOP('',(#1306,#1307,#1308,#1309));
#1311=FACE_BOUND('',#1310,.T.);
#1312=ADVANCED_FACE('F654',(#1311),#1305,.F.);
#1313=CARTESIAN_POINT('',(56.5,0.,-13.8));
#1314=DIRECTION('',(-1.,0.,0.));
#1315=DIRECTION('',(0.,0.,-1.));
#1316=AXIS2_PLACEMENT_3D('',#1313,#1314,#1315);
#1317=PLANE('',#1316);
#1318=ORIENTED_EDGE('',*,*,#1005,.F.);
#1319=DIRECTION('',(0.,1.,0.));
#1320=VECTOR('',#1319,1.);
#1321=CARTESIAN_POINT('',(56.5,0.,-7.8));
#1322=LINE('',#1321,#1320);
#1323=EDGE_CURVE('E505',#252,#998,#1322,.T.);
#1324=ORIENTED_EDGE('',*,*,#1323,.F.);
#1325=ORIENTED_EDGE('',*,*,#327,.T.);
#1326=ORIENTED_EDGE('',*,*,#54,.T.);
#1327=EDGE_LOOP('',(#1318,#1324,#1325,#1326));
#1328=FACE_BOUND('',#1327,.T.);
#1329=ADVANCED_FACE('F245',(#1328),#1317,.F.);
#1330=CARTESIAN_POINT('',(58.,0.,-7.8));
#1331=DIRECTION('',(0.,1.,0.));
#1332=DIRECTION('',(0.,0.,-1.));
#1333=AXIS2_PLACEMENT_3D('',#1330,#1331,#1332);
#1334=CYLINDRICAL_SURFACE('',#1333,1.5);
#1335=ORIENTED_EDGE('',*,*,#999,.F.);
#1336=DIRECTION('',(0.,1.,0.));
#1337=VECTOR('',#1336,1.);
#1338=CARTESIAN_POINT('',(59.5,0.,-7.8));
#1339=LINE('',#1338,#1337);
#1340=EDGE_CURVE('E508',#250,#989,#1339,.T.);
#1341=ORIENTED_EDGE('',*,*,#1340,.F.);
#1342=ORIENTED_EDGE('',*,*,#253,.T.);
#1343=ORIENTED_EDGE('',*,*,#1323,.T.);
#1344=EDGE_LOOP('',(#1335,#1341,#1342,#1343));
#1345=FACE_BOUND('',#1344,.T.);
#1346=ADVANCED_FACE('F656',(#1345),#1334,.F.);
#1347=CARTESIAN_POINT('',(59.5,0.,-7.8));
#1348=DIRECTION('',(1.,0.,0.));
#1349=DIRECTION('',(0.,0.,1.));
#1350=AXIS2_PLACEMENT_3D('',#1347,#1348,#1349);
#1351=PLANE('',#1350);
#1352=ORIENTED_EDGE('',*,*,#990,.F.);
#1353=ORIENTED_EDGE('',*,*,#925,.F.);
#1354=ORIENTED_EDGE('',*,*,#261,.T.);
#1355=ORIENTED_EDGE('',*,*,#1340,.T.);
#1356=EDGE_LOOP('',(#1352,#1353,#1354,#1355));
#1357=FACE_BOUND('',#1356,.T.);
#1358=ADVANCED_FACE('F657',(#1357),#1351,.F.);
#1359=CARTESIAN_POINT('',(3.575,17.,0.));
#1360=DIRECTION('',(0.,0.,-1.));
#1361=DIRECTION('',(1.,0.,0.));
#1362=AXIS2_PLACEMENT_3D('',#1359,#1360,#1361);
#1363=CYLINDRICAL_SURFACE('',#1362,1.575);
#1364=ORIENTED_EDGE('',*,*,#807,.T.);
#1365=EDGE_LOOP('',(#1364));
#1366=FACE_BOUND('',#1365,.T.);
#1367=ORIENTED_EDGE('',*,*,#547,.F.);
#1368=EDGE_LOOP('',(#1367));
#1369=FACE_BOUND('',#1368,.T.);
#1370=ADVANCED_FACE('F659',(#1366,#1369),#1363,.F.);
#1371=CARTESIAN_POINT('',(28.425,17.,0.));
#1372=DIRECTION('',(0.,0.,-1.));
#1373=DIRECTION('',(1.,0.,0.));
#1374=AXIS2_PLACEMENT_3D('',#1371,#1372,#1373);
#1375=CYLINDRICAL_SURFACE('',#1374,1.4);
#1376=ORIENTED_EDGE('',*,*,#796,.T.);
#1377=EDGE_LOOP('',(#1376));
#1378=FACE_BOUND('',#1377,.T.);
#1379=ORIENTED_EDGE('',*,*,#536,.F.);
#1380=EDGE_LOOP('',(#1379));
#1381=FACE_BOUND('',#1380,.T.);
#1382=ADVANCED_FACE('F665',(#1378,#1381),#1375,.F.);
#1383=CARTESIAN_POINT('',(33.425,17.,0.));
#1384=DIRECTION('',(0.,0.,-1.));
#1385=DIRECTION('',(1.,0.,0.));
#1386=AXIS2_PLACEMENT_3D('',#1383,#1384,#1385);
#1387=CYLINDRICAL_SURFACE('',#1386,1.575);
#1388=ORIENTED_EDGE('',*,*,#785,.T.);
#1389=EDGE_LOOP('',(#1388));
#1390=FACE_BOUND('',#1389,.T.);
#1391=ORIENTED_EDGE('',*,*,#525,.F.);
#1392=EDGE_LOOP('',(#1391));
#1393=FACE_BOUND('',#1392,.T.);
#1394=ADVANCED_FACE('F815',(#1390,#1393),#1387,.F.);
#1395=CARTESIAN_POINT('',(38.425,17.,0.));
#1396=DIRECTION('',(0.,0.,-1.));
#1397=DIRECTION('',(1.,0.,0.));
#1398=AXIS2_PLACEMENT_3D('',#1395,#1396,#1397);
#1399=CYLINDRICAL_SURFACE('',#1398,1.575);
#1400=ORIENTED_EDGE('',*,*,#774,.T.);
#1401=EDGE_LOOP('',(#1400));
#1402=FACE_BOUND('',#1401,.T.);
#1403=ORIENTED_EDGE('',*,*,#514,.F.);
#1404=EDGE_LOOP('',(#1403));
#1405=FACE_BOUND('',#1404,.T.);
#1406=ADVANCED_FACE('F825',(#1402,#1405),#1399,.F.);
#1407=CARTESIAN_POINT('',(43.425,17.,0.));
#1408=DIRECTION('',(0.,0.,-1.));
#1409=DIRECTION('',(1.,0.,0.));
#1410=AXIS2_PLACEMENT_3D('',#1407,#1408,#1409);
#1411=CYLINDRICAL_SURFACE('',#1410,1.575);
#1412=ORIENTED_EDGE('',*,*,#763,.T.);
#1413=EDGE_LOOP('',(#1412));
#1414=FACE_BOUND('',#1413,.T.);
#1415=ORIENTED_EDGE('',*,*,#503,.F.);
#1416=EDGE_LOOP('',(#1415));
#1417=FACE_BOUND('',#1416,.T.);
#1418=ADVANCED_FACE('F835',(#1414,#1417),#1411,.F.);
#1419=CARTESIAN_POINT('',(48.425,17.,0.));
#1420=DIRECTION('',(0.,0.,-1.));
#1421=DIRECTION('',(1.,0.,0.));
#1422=AXIS2_PLACEMENT_3D('',#1419,#1420,#1421);
#1423=CYLINDRICAL_SURFACE('',#1422,1.575);
#1424=ORIENTED_EDGE('',*,*,#752,.T.);
#1425=EDGE_LOOP('',(#1424));
#1426=FACE_BOUND('',#1425,.T.);
#1427=ORIENTED_EDGE('',*,*,#492,.F.);
#1428=EDGE_LOOP('',(#1427));
#1429=FACE_BOUND('',#1428,.T.);
#1430=ADVANCED_FACE('F845',(#1426,#1429),#1423,.F.);
#1431=CARTESIAN_POINT('',(53.425,17.,0.));
#1432=DIRECTION('',(0.,0.,-1.));
#1433=DIRECTION('',(1.,0.,0.));
#1434=AXIS2_PLACEMENT_3D('',#1431,#1432,#1433);
#1435=CYLINDRICAL_SURFACE('',#1434,1.575);
#1436=ORIENTED_EDGE('',*,*,#741,.T.);
#1437=EDGE_LOOP('',(#1436));
#1438=FACE_BOUND('',#1437,.T.);
#1439=ORIENTED_EDGE('',*,*,#481,.F.);
#1440=EDGE_LOOP('',(#1439));
#1441=FACE_BOUND('',#1440,.T.);
#1442=ADVANCED_FACE('F855',(#1438,#1441),#1435,.F.);
#1443=CARTESIAN_POINT('',(44.5,7.075,0.));
#1444=DIRECTION('',(0.,0.,-1.));
#1445=DIRECTION('',(1.,0.,0.));
#1446=AXIS2_PLACEMENT_3D('',#1443,#1444,#1445);
#1447=CYLINDRICAL_SURFACE('',#1446,1.57499999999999);
#1448=ORIENTED_EDGE('',*,*,#730,.T.);
#1449=EDGE_LOOP('',(#1448));
#1450=FACE_BOUND('',#1449,.T.);
#1451=ORIENTED_EDGE('',*,*,#470,.F.);
#1452=EDGE_LOOP('',(#1451));
#1453=FACE_BOUND('',#1452,.T.);
#1454=ADVANCED_FACE('F865',(#1450,#1453),#1447,.F.);
#1455=CARTESIAN_POINT('',(39.5,7.075,0.));
#1456=DIRECTION('',(0.,0.,-1.));
#1457=DIRECTION('',(1.,0.,0.));
#1458=AXIS2_PLACEMENT_3D('',#1455,#1456,#1457);
#1459=CYLINDRICAL_SURFACE('',#1458,1.575);
#1460=ORIENTED_EDGE('',*,*,#719,.T.);
#1461=EDGE_LOOP('',(#1460));
#1462=FACE_BOUND('',#1461,.T.);
#1463=ORIENTED_EDGE('',*,*,#459,.F.);
#1464=EDGE_LOOP('',(#1463));
#1465=FACE_BOUND('',#1464,.T.);
#1466=ADVANCED_FACE('F875',(#1462,#1465),#1459,.F.);
#1467=CARTESIAN_POINT('',(29.5,7.075,0.));
#1468=DIRECTION('',(0.,0.,-1.));
#1469=DIRECTION('',(1.,0.,0.));
#1470=AXIS2_PLACEMENT_3D('',#1467,#1468,#1469);
#1471=CYLINDRICAL_SURFACE('',#1470,1.575);
#1472=ORIENTED_EDGE('',*,*,#708,.T.);
#1473=EDGE_LOOP('',(#1472));
#1474=FACE_BOUND('',#1473,.T.);
#1475=ORIENTED_EDGE('',*,*,#448,.F.);
#1476=EDGE_LOOP('',(#1475));
#1477=FACE_BOUND('',#1476,.T.);
#1478=ADVANCED_FACE('F885',(#1474,#1477),#1471,.F.);
#1479=CARTESIAN_POINT('',(29.5,27.125,0.));
#1480=DIRECTION('',(0.,0.,-1.));
#1481=DIRECTION('',(1.,0.,0.));
#1482=AXIS2_PLACEMENT_3D('',#1479,#1480,#1481);
#1483=CYLINDRICAL_SURFACE('',#1482,1.575);
#1484=ORIENTED_EDGE('',*,*,#697,.T.);
#1485=EDGE_LOOP('',(#1484));
#1486=FACE_BOUND('',#1485,.T.);
#1487=ORIENTED_EDGE('',*,*,#437,.F.);
#1488=EDGE_LOOP('',(#1487));
#1489=FACE_BOUND('',#1488,.T.);
#1490=ADVANCED_FACE('F895',(#1486,#1489),#1483,.F.);
#1491=CARTESIAN_POINT('',(39.5,27.125,0.));
#1492=DIRECTION('',(0.,0.,-1.));
#1493=DIRECTION('',(1.,0.,0.));
#1494=AXIS2_PLACEMENT_3D('',#1491,#1492,#1493);
#1495=CYLINDRICAL_SURFACE('',#1494,1.575);
#1496=ORIENTED_EDGE('',*,*,#686,.T.);
#1497=EDGE_LOOP('',(#1496));
#1498=FACE_BOUND('',#1497,.T.);
#1499=ORIENTED_EDGE('',*,*,#426,.F.);
#1500=EDGE_LOOP('',(#1499));
#1501=FACE_BOUND('',#1500,.T.);
#1502=ADVANCED_FACE('F905',(#1498,#1501),#1495,.F.);
#1503=CARTESIAN_POINT('',(44.5,27.125,0.));
#1504=DIRECTION('',(0.,0.,-1.));
#1505=DIRECTION('',(1.,0.,0.));
#1506=AXIS2_PLACEMENT_3D('',#1503,#1504,#1505);
#1507=CYLINDRICAL_SURFACE('',#1506,1.57499999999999);
#1508=ORIENTED_EDGE('',*,*,#675,.T.);
#1509=EDGE_LOOP('',(#1508));
#1510=FACE_BOUND('',#1509,.T.);
#1511=ORIENTED_EDGE('',*,*,#415,.F.);
#1512=EDGE_LOOP('',(#1511));
#1513=FACE_BOUND('',#1512,.T.);
#1514=ADVANCED_FACE('F915',(#1510,#1513),#1507,.F.);
#1515=CARTESIAN_POINT('',(59.425,17.,0.));
#1516=DIRECTION('',(0.,0.,-1.));
#1517=DIRECTION('',(1.,0.,0.));
#1518=AXIS2_PLACEMENT_3D('',#1515,#1516,#1517);
#1519=CYLINDRICAL_SURFACE('',#1518,1.575);
#1520=ORIENTED_EDGE('',*,*,#664,.T.);
#1521=EDGE_LOOP('',(#1520));
#1522=FACE_BOUND('',#1521,.T.);
#1523=ORIENTED_EDGE('',*,*,#404,.F.);
#1524=EDGE_LOOP('',(#1523));
#1525=FACE_BOUND('',#1524,.T.);
#1526=ADVANCED_FACE('F625',(#1522,#1525),#1519,.F.);
#1527=CARTESIAN_POINT('',(53.5,27.125,0.));
#1528=DIRECTION('',(0.,0.,-1.));
#1529=DIRECTION('',(1.,0.,0.));
#1530=AXIS2_PLACEMENT_3D('',#1527,#1528,#1529);
#1531=CYLINDRICAL_SURFACE('',#1530,1.575);
#1532=ORIENTED_EDGE('',*,*,#653,.T.);
#1533=EDGE_LOOP('',(#1532));
#1534=FACE_BOUND('',#1533,.T.);
#1535=ORIENTED_EDGE('',*,*,#393,.F.);
#1536=EDGE_LOOP('',(#1535));
#1537=FACE_BOUND('',#1536,.T.);
#1538=ADVANCED_FACE('F619',(#1534,#1537),#1531,.F.);
#1539=CARTESIAN_POINT('',(53.5,7.075,0.));
#1540=DIRECTION('',(0.,0.,-1.));
#1541=DIRECTION('',(1.,0.,0.));
#1542=AXIS2_PLACEMENT_3D('',#1539,#1540,#1541);
#1543=CYLINDRICAL_SURFACE('',#1542,1.575);
#1544=ORIENTED_EDGE('',*,*,#642,.T.);
#1545=EDGE_LOOP('',(#1544));
#1546=FACE_BOUND('',#1545,.T.);
#1547=ORIENTED_EDGE('',*,*,#382,.F.);
#1548=EDGE_LOOP('',(#1547));
#1549=FACE_BOUND('',#1548,.T.);
#1550=ADVANCED_FACE('F617',(#1546,#1549),#1543,.F.);
#1551=CLOSED_SHELL('',(#58,#85,#127,#158,#191,#238,#331,#369,#629,#889,#907,#929,#947,#1009,
#1041,#1072,#1089,#1122,#1147,#1178,#1195,#1221,#1239,#1251,#1259,#1266,#1283,#1300,#1312,#1329,
#1346,#1358,#1370,#1382,#1394,#1406,#1418,#1430,#1442,#1454,#1466,#1478,#1490,#1502,#1514,#1526,
#1538,#1550));
#1552=MANIFOLD_SOLID_BREP('B2',#1551);
#1553=ADVANCED_BREP_SHAPE_REPRESENTATION('',(#18,#1552),#14);
#1554=SHAPE_DEFINITION_REPRESENTATION(#9,#1553);
ENDSEC;
END-ISO-10303-21;
